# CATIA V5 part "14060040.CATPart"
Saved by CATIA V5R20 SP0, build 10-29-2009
Part number: 14060040
Definition: NONE
Nomenclature: 14060040
Source: Unknown
Description: 14060040
Bounding box of the stored display mesh (mm): x -20 to 80, y -44 to 33.913, z -34.1 to 34.1
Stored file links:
  C:\Users\Utente\Desktop\IO LAVORO\3D X SITO CF\X SITO\PLASTICA\RF2\14060040.CATPart

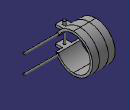
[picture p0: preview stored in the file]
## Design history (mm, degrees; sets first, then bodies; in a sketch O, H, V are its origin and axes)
Body1 "14060040" (main body)
  Solid1: solid without history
